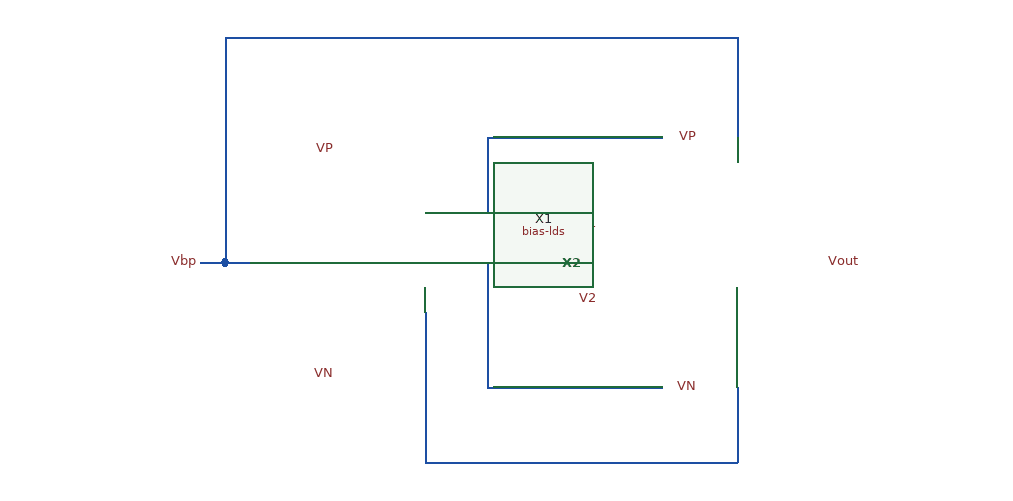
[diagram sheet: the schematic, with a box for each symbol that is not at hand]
v {xschem version=2.9.9 file_version=1.2 }
G {}
K {}
V {}
S {}
E {}
N 6080 -360 6130 -360 { lab=#net1}
N 6130 -360 6130 -260 { lab=#net1}
N 6080 -400 6130 -400 { lab=#net2}
N 6130 -460 6130 -400 { lab=#net2}
N 6080 -320 6080 -200 { lab=#net3}
N 5920 -360 5940 -360 { lab=Vbp}
N 5920 -540 5920 -360 { lab=Vbp}
N 5920 -540 6330 -540 { lab=Vbp}
N 5900 -360 5920 -360 { lab=Vbp}
N 6330 -540 6330 -460 { lab=Vbp}
N 6330 -260 6330 -200 { lab=#net3}
N 6150 -460 6270 -460 { lab=#net2}
N 6240 -260 6270 -260 { lab=#net1}
N 6130 -460 6150 -460 { lab=#net2}
N 6130 -260 6240 -260 { lab=#net1}
N 6080 -200 6330 -200 { lab=#net3}
C {devices/lab_pin.sym} 6400 -360 2 0 {name=l5 sig_type=std_logic lab=Vout}
C {devices/lab_pin.sym} 6220 -390 0 0 {name=l6 sig_type=std_logic lab=V1}
C {devices/lab_pin.sym} 6220 -330 0 0 {name=l7 sig_type=std_logic lab=V2}
C {devices/lab_pin.sym} 5900 -360 0 0 {name=l8 sig_type=std_logic lab=Vbp}
C {/home/madvlsi/Desktop/madvlsi/MP3/simulations/bias-lds.sym} 5830 -360 0 0 {name=X1}
C {/home/madvlsi/Desktop/madvlsi/MP3/simulations/cascode-lds.sym} 6190 -360 0 0 {name=X2}
C {devices/lab_pin.sym} 6010 -450 0 0 {name=l1 sig_type=std_logic lab=VP}
C {devices/lab_pin.sym} 6010 -270 0 0 {name=l2 sig_type=std_logic lab=VN}
C {devices/lab_pin.sym} 6300 -460 1 0 {name=l3 sig_type=std_logic lab=VP}
C {devices/lab_pin.sym} 6300 -260 3 0 {name=l4 sig_type=std_logic lab=VN}
